##
## LEF for PtnCells ;
## created by Innovus v15.23-s045_1 on Thu Mar  5 10:42:21 2026
##

VERSION 5.8 ;

BUSBITCHARS "[]" ;
DIVIDERCHAR "/" ;

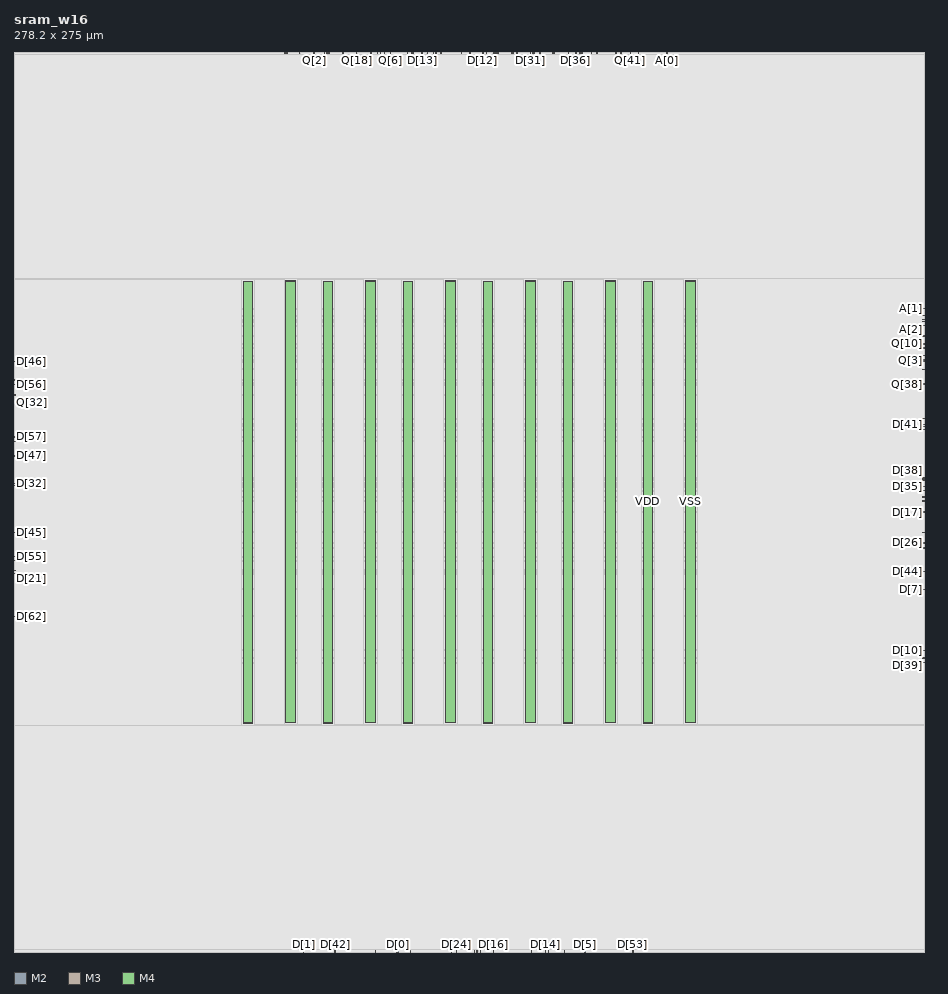
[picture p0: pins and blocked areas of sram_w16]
MACRO sram_w16
  CLASS BLOCK ;
  SIZE 278.2000 BY 275.0000 ;
  FOREIGN sram_w16 0.0000 0.0000 ;
  ORIGIN 0 0 ;
  SYMMETRY X Y R90 ;
  PIN CLK
    DIRECTION INPUT ;
    USE SIGNAL ;
    PORT
      LAYER M2 ;
        RECT 141.4500 0.0000 141.5500 0.5200 ;
    END
  END CLK
  PIN D[63]
    DIRECTION INPUT ;
    USE SIGNAL ;
    PORT
      LAYER M2 ;
        RECT 116.8500 0.0000 116.9500 0.5200 ;
    END
  END D[63]
  PIN D[62]
    DIRECTION INPUT ;
    USE SIGNAL ;
    PORT
      LAYER M3 ;
        RECT 0.0000 102.5500 0.5200 102.6500 ;
    END
  END D[62]
  PIN D[61]
    DIRECTION INPUT ;
    USE SIGNAL ;
    PORT
      LAYER M2 ;
        RECT 146.6500 274.4800 146.7500 275.0000 ;
    END
  END D[61]
  PIN D[60]
    DIRECTION INPUT ;
    USE SIGNAL ;
    PORT
      LAYER M3 ;
        RECT 277.6800 140.9500 278.2000 141.0500 ;
    END
  END D[60]
  PIN D[59]
    DIRECTION INPUT ;
    USE SIGNAL ;
    PORT
      LAYER M2 ;
        RECT 176.4500 274.4800 176.5500 275.0000 ;
    END
  END D[59]
  PIN D[58]
    DIRECTION INPUT ;
    USE SIGNAL ;
    PORT
      LAYER M3 ;
        RECT 0.0000 174.7500 0.5200 174.8500 ;
    END
  END D[58]
  PIN D[57]
    DIRECTION INPUT ;
    USE SIGNAL ;
    PORT
      LAYER M3 ;
        RECT 0.0000 157.3500 0.5200 157.4500 ;
    END
  END D[57]
  PIN D[56]
    DIRECTION INPUT ;
    USE SIGNAL ;
    PORT
      LAYER M3 ;
        RECT 0.0000 173.3500 0.5200 173.4500 ;
    END
  END D[56]
  PIN D[55]
    DIRECTION INPUT ;
    USE SIGNAL ;
    PORT
      LAYER M3 ;
        RECT 0.0000 120.7500 0.5200 120.8500 ;
    END
  END D[55]
  PIN D[54]
    DIRECTION INPUT ;
    USE SIGNAL ;
    PORT
      LAYER M2 ;
        RECT 142.4500 0.0000 142.5500 0.5200 ;
    END
  END D[54]
  PIN D[53]
    DIRECTION INPUT ;
    USE SIGNAL ;
    PORT
      LAYER M2 ;
        RECT 189.0500 0.0000 189.1500 0.5200 ;
    END
  END D[53]
  PIN D[52]
    DIRECTION INPUT ;
    USE SIGNAL ;
    PORT
      LAYER M3 ;
        RECT 277.6800 159.5500 278.2000 159.6500 ;
    END
  END D[52]
  PIN D[51]
    DIRECTION INPUT ;
    USE SIGNAL ;
    PORT
      LAYER M3 ;
        RECT 277.6800 88.3500 278.2000 88.4500 ;
    END
  END D[51]
  PIN D[50]
    DIRECTION INPUT ;
    USE SIGNAL ;
    PORT
      LAYER M4 ;
        RECT 141.6500 0.0000 141.7500 0.5200 ;
    END
  END D[50]
  PIN D[49]
    DIRECTION INPUT ;
    USE SIGNAL ;
    PORT
      LAYER M3 ;
        RECT 277.6800 144.1500 278.2000 144.2500 ;
    END
  END D[49]
  PIN D[48]
    DIRECTION INPUT ;
    USE SIGNAL ;
    PORT
      LAYER M3 ;
        RECT 0.0000 142.5500 0.5200 142.6500 ;
    END
  END D[48]
  PIN D[47]
    DIRECTION INPUT ;
    USE SIGNAL ;
    PORT
      LAYER M3 ;
        RECT 0.0000 151.5500 0.5200 151.6500 ;
    END
  END D[47]
  PIN D[46]
    DIRECTION INPUT ;
    USE SIGNAL ;
    PORT
      LAYER M3 ;
        RECT 0.0000 180.3500 0.5200 180.4500 ;
    END
  END D[46]
  PIN D[45]
    DIRECTION INPUT ;
    USE SIGNAL ;
    PORT
      LAYER M3 ;
        RECT 0.0000 128.1500 0.5200 128.2500 ;
    END
  END D[45]
  PIN D[44]
    DIRECTION INPUT ;
    USE SIGNAL ;
    PORT
      LAYER M3 ;
        RECT 277.6800 116.1500 278.2000 116.2500 ;
    END
  END D[44]
  PIN D[43]
    DIRECTION INPUT ;
    USE SIGNAL ;
    PORT
      LAYER M3 ;
        RECT 0.0000 115.5500 0.5200 115.6500 ;
    END
  END D[43]
  PIN D[42]
    DIRECTION INPUT ;
    USE SIGNAL ;
    PORT
      LAYER M2 ;
        RECT 98.0500 0.0000 98.1500 0.5200 ;
    END
  END D[42]
  PIN D[41]
    DIRECTION INPUT ;
    USE SIGNAL ;
    PORT
      LAYER M3 ;
        RECT 277.6800 161.1500 278.2000 161.2500 ;
    END
  END D[41]
  PIN D[40]
    DIRECTION INPUT ;
    USE SIGNAL ;
    PORT
      LAYER M2 ;
        RECT 140.6500 0.0000 140.7500 0.5200 ;
    END
  END D[40]
  PIN D[39]
    DIRECTION INPUT ;
    USE SIGNAL ;
    PORT
      LAYER M3 ;
        RECT 277.6800 89.7500 278.2000 89.8500 ;
    END
  END D[39]
  PIN D[38]
    DIRECTION INPUT ;
    USE SIGNAL ;
    PORT
      LAYER M3 ;
        RECT 277.6800 144.7500 278.2000 144.8500 ;
    END
  END D[38]
  PIN D[37]
    DIRECTION INPUT ;
    USE SIGNAL ;
    PORT
      LAYER M2 ;
        RECT 158.4500 274.4800 158.5500 275.0000 ;
    END
  END D[37]
  PIN D[36]
    DIRECTION INPUT ;
    USE SIGNAL ;
    PORT
      LAYER M2 ;
        RECT 171.6500 274.4800 171.7500 275.0000 ;
    END
  END D[36]
  PIN D[35]
    DIRECTION INPUT ;
    USE SIGNAL ;
    PORT
      LAYER M3 ;
        RECT 277.6800 142.1500 278.2000 142.2500 ;
    END
  END D[35]
  PIN D[34]
    DIRECTION INPUT ;
    USE SIGNAL ;
    PORT
      LAYER M2 ;
        RECT 164.6500 274.4800 164.7500 275.0000 ;
    END
  END D[34]
  PIN D[33]
    DIRECTION INPUT ;
    USE SIGNAL ;
    PORT
      LAYER M2 ;
        RECT 128.8500 274.4800 128.9500 275.0000 ;
    END
  END D[33]
  PIN D[32]
    DIRECTION INPUT ;
    USE SIGNAL ;
    PORT
      LAYER M3 ;
        RECT 0.0000 143.1500 0.5200 143.2500 ;
    END
  END D[32]
  PIN D[31]
    DIRECTION INPUT ;
    USE SIGNAL ;
    PORT
      LAYER M2 ;
        RECT 157.8500 274.4800 157.9500 275.0000 ;
    END
  END D[31]
  PIN D[30]
    DIRECTION INPUT ;
    USE SIGNAL ;
    PORT
      LAYER M2 ;
        RECT 144.2500 274.4800 144.3500 275.0000 ;
    END
  END D[30]
  PIN D[29]
    DIRECTION INPUT ;
    USE SIGNAL ;
    PORT
      LAYER M2 ;
        RECT 185.4500 274.4800 185.5500 275.0000 ;
    END
  END D[29]
  PIN D[28]
    DIRECTION INPUT ;
    USE SIGNAL ;
    PORT
      LAYER M3 ;
        RECT 277.6800 128.1500 278.2000 128.2500 ;
    END
  END D[28]
  PIN D[27]
    DIRECTION INPUT ;
    USE SIGNAL ;
    PORT
      LAYER M4 ;
        RECT 146.4500 274.4800 146.5500 275.0000 ;
    END
  END D[27]
  PIN D[26]
    DIRECTION INPUT ;
    USE SIGNAL ;
    PORT
      LAYER M3 ;
        RECT 277.6800 124.9500 278.2000 125.0500 ;
    END
  END D[26]
  PIN D[25]
    DIRECTION INPUT ;
    USE SIGNAL ;
    PORT
      LAYER M2 ;
        RECT 128.0500 274.4800 128.1500 275.0000 ;
    END
  END D[25]
  PIN D[24]
    DIRECTION INPUT ;
    USE SIGNAL ;
    PORT
      LAYER M2 ;
        RECT 135.2500 0.0000 135.3500 0.5200 ;
    END
  END D[24]
  PIN D[23]
    DIRECTION INPUT ;
    USE SIGNAL ;
    PORT
      LAYER M2 ;
        RECT 168.2500 0.0000 168.3500 0.5200 ;
    END
  END D[23]
  PIN D[22]
    DIRECTION INPUT ;
    USE SIGNAL ;
    PORT
      LAYER M2 ;
        RECT 111.0500 274.4800 111.1500 275.0000 ;
    END
  END D[22]
  PIN D[21]
    DIRECTION INPUT ;
    USE SIGNAL ;
    PORT
      LAYER M3 ;
        RECT 0.0000 116.5500 0.5200 116.6500 ;
    END
  END D[21]
  PIN D[20]
    DIRECTION INPUT ;
    USE SIGNAL ;
    PORT
      LAYER M2 ;
        RECT 111.8500 274.4800 111.9500 275.0000 ;
    END
  END D[20]
  PIN D[19]
    DIRECTION INPUT ;
    USE SIGNAL ;
    PORT
      LAYER M2 ;
        RECT 158.0500 0.0000 158.1500 0.5200 ;
    END
  END D[19]
  PIN D[18]
    DIRECTION INPUT ;
    USE SIGNAL ;
    PORT
      LAYER M2 ;
        RECT 94.8500 274.4800 94.9500 275.0000 ;
    END
  END D[18]
  PIN D[17]
    DIRECTION INPUT ;
    USE SIGNAL ;
    PORT
      LAYER M3 ;
        RECT 277.6800 134.3500 278.2000 134.4500 ;
    END
  END D[17]
  PIN D[16]
    DIRECTION INPUT ;
    USE SIGNAL ;
    PORT
      LAYER M2 ;
        RECT 146.4500 0.0000 146.5500 0.5200 ;
    END
  END D[16]
  PIN D[15]
    DIRECTION INPUT ;
    USE SIGNAL ;
    PORT
      LAYER M2 ;
        RECT 163.2500 0.0000 163.3500 0.5200 ;
    END
  END D[15]
  PIN D[14]
    DIRECTION INPUT ;
    USE SIGNAL ;
    PORT
      LAYER M2 ;
        RECT 162.2500 0.0000 162.3500 0.5200 ;
    END
  END D[14]
  PIN D[13]
    DIRECTION INPUT ;
    USE SIGNAL ;
    PORT
      LAYER M2 ;
        RECT 124.6500 274.4800 124.7500 275.0000 ;
    END
  END D[13]
  PIN D[12]
    DIRECTION INPUT ;
    USE SIGNAL ;
    PORT
      LAYER M2 ;
        RECT 143.2500 274.4800 143.3500 275.0000 ;
    END
  END D[12]
  PIN D[11]
    DIRECTION INPUT ;
    USE SIGNAL ;
    PORT
      LAYER M2 ;
        RECT 130.4500 274.4800 130.5500 275.0000 ;
    END
  END D[11]
  PIN D[10]
    DIRECTION INPUT ;
    USE SIGNAL ;
    PORT
      LAYER M3 ;
        RECT 277.6800 92.1500 278.2000 92.2500 ;
    END
  END D[10]
  PIN D[9]
    DIRECTION INPUT ;
    USE SIGNAL ;
    PORT
      LAYER M3 ;
        RECT 0.0000 155.9500 0.5200 156.0500 ;
    END
  END D[9]
  PIN D[8]
    DIRECTION INPUT ;
    USE SIGNAL ;
    PORT
      LAYER M2 ;
        RECT 133.6500 0.0000 133.7500 0.5200 ;
    END
  END D[8]
  PIN D[7]
    DIRECTION INPUT ;
    USE SIGNAL ;
    PORT
      LAYER M3 ;
        RECT 277.6800 110.7500 278.2000 110.8500 ;
    END
  END D[7]
  PIN D[6]
    DIRECTION INPUT ;
    USE SIGNAL ;
    PORT
      LAYER M2 ;
        RECT 121.0500 0.0000 121.1500 0.5200 ;
    END
  END D[6]
  PIN D[5]
    DIRECTION INPUT ;
    USE SIGNAL ;
    PORT
      LAYER M2 ;
        RECT 174.4500 0.0000 174.5500 0.5200 ;
    END
  END D[5]
  PIN D[4]
    DIRECTION INPUT ;
    USE SIGNAL ;
    PORT
      LAYER M2 ;
        RECT 110.4500 0.0000 110.5500 0.5200 ;
    END
  END D[4]
  PIN D[3]
    DIRECTION INPUT ;
    USE SIGNAL ;
    PORT
      LAYER M3 ;
        RECT 277.6800 177.9500 278.2000 178.0500 ;
    END
  END D[3]
  PIN D[2]
    DIRECTION INPUT ;
    USE SIGNAL ;
    PORT
      LAYER M3 ;
        RECT 0.0000 119.5500 0.5200 119.6500 ;
    END
  END D[2]
  PIN D[1]
    DIRECTION INPUT ;
    USE SIGNAL ;
    PORT
      LAYER M2 ;
        RECT 88.4500 0.0000 88.5500 0.5200 ;
    END
  END D[1]
  PIN D[0]
    DIRECTION INPUT ;
    USE SIGNAL ;
    PORT
      LAYER M2 ;
        RECT 117.2500 0.0000 117.3500 0.5200 ;
    END
  END D[0]
  PIN Q[63]
    DIRECTION OUTPUT ;
    USE SIGNAL ;
    PORT
      LAYER M2 ;
        RECT 121.8500 274.4800 121.9500 275.0000 ;
    END
  END Q[63]
  PIN Q[62]
    DIRECTION OUTPUT ;
    USE SIGNAL ;
    PORT
      LAYER M2 ;
        RECT 83.0500 274.4800 83.1500 275.0000 ;
    END
  END Q[62]
  PIN Q[61]
    DIRECTION OUTPUT ;
    USE SIGNAL ;
    PORT
      LAYER M2 ;
        RECT 147.8500 274.4800 147.9500 275.0000 ;
    END
  END Q[61]
  PIN Q[60]
    DIRECTION OUTPUT ;
    USE SIGNAL ;
    PORT
      LAYER M3 ;
        RECT 277.6800 162.9500 278.2000 163.0500 ;
    END
  END Q[60]
  PIN Q[59]
    DIRECTION OUTPUT ;
    USE SIGNAL ;
    PORT
      LAYER M2 ;
        RECT 183.8500 274.4800 183.9500 275.0000 ;
    END
  END Q[59]
  PIN Q[58]
    DIRECTION OUTPUT ;
    USE SIGNAL ;
    PORT
      LAYER M2 ;
        RECT 87.2500 274.4800 87.3500 275.0000 ;
    END
  END Q[58]
  PIN Q[57]
    DIRECTION OUTPUT ;
    USE SIGNAL ;
    PORT
      LAYER M2 ;
        RECT 113.2500 274.4800 113.3500 275.0000 ;
    END
  END Q[57]
  PIN Q[56]
    DIRECTION OUTPUT ;
    USE SIGNAL ;
    PORT
      LAYER M2 ;
        RECT 95.8500 274.4800 95.9500 275.0000 ;
    END
  END Q[56]
  PIN Q[55]
    DIRECTION OUTPUT ;
    USE SIGNAL ;
    PORT
      LAYER M4 ;
        RECT 95.8500 274.4800 95.9500 275.0000 ;
    END
  END Q[55]
  PIN Q[54]
    DIRECTION OUTPUT ;
    USE SIGNAL ;
    PORT
      LAYER M2 ;
        RECT 147.0500 274.4800 147.1500 275.0000 ;
    END
  END Q[54]
  PIN Q[53]
    DIRECTION OUTPUT ;
    USE SIGNAL ;
    PORT
      LAYER M3 ;
        RECT 277.6800 160.5500 278.2000 160.6500 ;
    END
  END Q[53]
  PIN Q[52]
    DIRECTION OUTPUT ;
    USE SIGNAL ;
    PORT
      LAYER M2 ;
        RECT 190.8500 274.4800 190.9500 275.0000 ;
    END
  END Q[52]
  PIN Q[51]
    DIRECTION OUTPUT ;
    USE SIGNAL ;
    PORT
      LAYER M3 ;
        RECT 277.6800 180.9500 278.2000 181.0500 ;
    END
  END Q[51]
  PIN Q[50]
    DIRECTION OUTPUT ;
    USE SIGNAL ;
    PORT
      LAYER M4 ;
        RECT 164.8500 274.4800 164.9500 275.0000 ;
    END
  END Q[50]
  PIN Q[49]
    DIRECTION OUTPUT ;
    USE SIGNAL ;
    PORT
      LAYER M3 ;
        RECT 277.6800 182.1500 278.2000 182.2500 ;
    END
  END Q[49]
  PIN Q[48]
    DIRECTION OUTPUT ;
    USE SIGNAL ;
    PORT
      LAYER M2 ;
        RECT 100.6500 274.4800 100.7500 275.0000 ;
    END
  END Q[48]
  PIN Q[47]
    DIRECTION OUTPUT ;
    USE SIGNAL ;
    PORT
      LAYER M4 ;
        RECT 83.0500 274.4800 83.1500 275.0000 ;
    END
  END Q[47]
  PIN Q[46]
    DIRECTION OUTPUT ;
    USE SIGNAL ;
    PORT
      LAYER M2 ;
        RECT 95.4500 274.4800 95.5500 275.0000 ;
    END
  END Q[46]
  PIN Q[45]
    DIRECTION OUTPUT ;
    USE SIGNAL ;
    PORT
      LAYER M4 ;
        RECT 130.4500 274.4800 130.5500 275.0000 ;
    END
  END Q[45]
  PIN Q[44]
    DIRECTION OUTPUT ;
    USE SIGNAL ;
    PORT
      LAYER M3 ;
        RECT 277.6800 173.7500 278.2000 173.8500 ;
    END
  END Q[44]
  PIN Q[43]
    DIRECTION OUTPUT ;
    USE SIGNAL ;
    PORT
      LAYER M4 ;
        RECT 87.2500 274.4800 87.3500 275.0000 ;
    END
  END Q[43]
  PIN Q[42]
    DIRECTION OUTPUT ;
    USE SIGNAL ;
    PORT
      LAYER M2 ;
        RECT 82.6500 274.4800 82.7500 275.0000 ;
    END
  END Q[42]
  PIN Q[41]
    DIRECTION OUTPUT ;
    USE SIGNAL ;
    PORT
      LAYER M2 ;
        RECT 188.2500 274.4800 188.3500 275.0000 ;
    END
  END Q[41]
  PIN Q[40]
    DIRECTION OUTPUT ;
    USE SIGNAL ;
    PORT
      LAYER M2 ;
        RECT 153.6500 274.4800 153.7500 275.0000 ;
    END
  END Q[40]
  PIN Q[39]
    DIRECTION OUTPUT ;
    USE SIGNAL ;
    PORT
      LAYER M3 ;
        RECT 277.6800 185.7500 278.2000 185.8500 ;
    END
  END Q[39]
  PIN Q[38]
    DIRECTION OUTPUT ;
    USE SIGNAL ;
    PORT
      LAYER M3 ;
        RECT 277.6800 173.3500 278.2000 173.4500 ;
    END
  END Q[38]
  PIN Q[37]
    DIRECTION OUTPUT ;
    USE SIGNAL ;
    PORT
      LAYER M2 ;
        RECT 152.0500 274.4800 152.1500 275.0000 ;
    END
  END Q[37]
  PIN Q[36]
    DIRECTION OUTPUT ;
    USE SIGNAL ;
    PORT
      LAYER M2 ;
        RECT 173.6500 274.4800 173.7500 275.0000 ;
    END
  END Q[36]
  PIN Q[35]
    DIRECTION OUTPUT ;
    USE SIGNAL ;
    PORT
      LAYER M2 ;
        RECT 169.4500 274.4800 169.5500 275.0000 ;
    END
  END Q[35]
  PIN Q[34]
    DIRECTION OUTPUT ;
    USE SIGNAL ;
    PORT
      LAYER M2 ;
        RECT 158.8500 274.4800 158.9500 275.0000 ;
    END
  END Q[34]
  PIN Q[33]
    DIRECTION OUTPUT ;
    USE SIGNAL ;
    PORT
      LAYER M2 ;
        RECT 139.2500 274.4800 139.3500 275.0000 ;
    END
  END Q[33]
  PIN Q[32]
    DIRECTION OUTPUT ;
    USE SIGNAL ;
    PORT
      LAYER M3 ;
        RECT 0.0000 170.1500 0.5200 170.2500 ;
    END
  END Q[32]
  PIN Q[31]
    DIRECTION OUTPUT ;
    USE SIGNAL ;
    PORT
      LAYER M2 ;
        RECT 160.6500 274.4800 160.7500 275.0000 ;
    END
  END Q[31]
  PIN Q[30]
    DIRECTION OUTPUT ;
    USE SIGNAL ;
    PORT
      LAYER M4 ;
        RECT 147.2500 274.4800 147.3500 275.0000 ;
    END
  END Q[30]
  PIN Q[29]
    DIRECTION OUTPUT ;
    USE SIGNAL ;
    PORT
      LAYER M2 ;
        RECT 178.0500 274.4800 178.1500 275.0000 ;
    END
  END Q[29]
  PIN Q[28]
    DIRECTION OUTPUT ;
    USE SIGNAL ;
    PORT
      LAYER M2 ;
        RECT 165.0500 274.4800 165.1500 275.0000 ;
    END
  END Q[28]
  PIN Q[27]
    DIRECTION OUTPUT ;
    USE SIGNAL ;
    PORT
      LAYER M2 ;
        RECT 152.4500 274.4800 152.5500 275.0000 ;
    END
  END Q[27]
  PIN Q[26]
    DIRECTION OUTPUT ;
    USE SIGNAL ;
    PORT
      LAYER M3 ;
        RECT 277.6800 138.9500 278.2000 139.0500 ;
    END
  END Q[26]
  PIN Q[25]
    DIRECTION OUTPUT ;
    USE SIGNAL ;
    PORT
      LAYER M2 ;
        RECT 126.2500 274.4800 126.3500 275.0000 ;
    END
  END Q[25]
  PIN Q[24]
    DIRECTION OUTPUT ;
    USE SIGNAL ;
    PORT
      LAYER M4 ;
        RECT 126.2500 274.4800 126.3500 275.0000 ;
    END
  END Q[24]
  PIN Q[23]
    DIRECTION OUTPUT ;
    USE SIGNAL ;
    PORT
      LAYER M3 ;
        RECT 277.6800 123.3500 278.2000 123.4500 ;
    END
  END Q[23]
  PIN Q[22]
    DIRECTION OUTPUT ;
    USE SIGNAL ;
    PORT
      LAYER M4 ;
        RECT 100.4500 274.4800 100.5500 275.0000 ;
    END
  END Q[22]
  PIN Q[21]
    DIRECTION OUTPUT ;
    USE SIGNAL ;
    PORT
      LAYER M2 ;
        RECT 104.6500 274.4800 104.7500 275.0000 ;
    END
  END Q[21]
  PIN Q[20]
    DIRECTION OUTPUT ;
    USE SIGNAL ;
    PORT
      LAYER M2 ;
        RECT 109.0500 274.4800 109.1500 275.0000 ;
    END
  END Q[20]
  PIN Q[19]
    DIRECTION OUTPUT ;
    USE SIGNAL ;
    PORT
      LAYER M4 ;
        RECT 152.0500 274.4800 152.1500 275.0000 ;
    END
  END Q[19]
  PIN Q[18]
    DIRECTION OUTPUT ;
    USE SIGNAL ;
    PORT
      LAYER M4 ;
        RECT 104.6500 274.4800 104.7500 275.0000 ;
    END
  END Q[18]
  PIN Q[17]
    DIRECTION OUTPUT ;
    USE SIGNAL ;
    PORT
      LAYER M3 ;
        RECT 277.6800 184.5500 278.2000 184.6500 ;
    END
  END Q[17]
  PIN Q[16]
    DIRECTION OUTPUT ;
    USE SIGNAL ;
    PORT
      LAYER M4 ;
        RECT 146.8500 274.4800 146.9500 275.0000 ;
    END
  END Q[16]
  PIN Q[15]
    DIRECTION OUTPUT ;
    USE SIGNAL ;
    PORT
      LAYER M4 ;
        RECT 173.6500 274.4800 173.7500 275.0000 ;
    END
  END Q[15]
  PIN Q[14]
    DIRECTION OUTPUT ;
    USE SIGNAL ;
    PORT
      LAYER M2 ;
        RECT 173.2500 274.4800 173.3500 275.0000 ;
    END
  END Q[14]
  PIN Q[13]
    DIRECTION OUTPUT ;
    USE SIGNAL ;
    PORT
      LAYER M4 ;
        RECT 109.0500 274.4800 109.1500 275.0000 ;
    END
  END Q[13]
  PIN Q[12]
    DIRECTION OUTPUT ;
    USE SIGNAL ;
    PORT
      LAYER M2 ;
        RECT 147.4500 274.4800 147.5500 275.0000 ;
    END
  END Q[12]
  PIN Q[11]
    DIRECTION OUTPUT ;
    USE SIGNAL ;
    PORT
      LAYER M2 ;
        RECT 120.2500 274.4800 120.3500 275.0000 ;
    END
  END Q[11]
  PIN Q[10]
    DIRECTION OUTPUT ;
    USE SIGNAL ;
    PORT
      LAYER M3 ;
        RECT 277.6800 188.1500 278.2000 188.2500 ;
    END
  END Q[10]
  PIN Q[9]
    DIRECTION OUTPUT ;
    USE SIGNAL ;
    PORT
      LAYER M2 ;
        RECT 83.4500 274.4800 83.5500 275.0000 ;
    END
  END Q[9]
  PIN Q[8]
    DIRECTION OUTPUT ;
    USE SIGNAL ;
    PORT
      LAYER M2 ;
        RECT 136.6500 274.4800 136.7500 275.0000 ;
    END
  END Q[8]
  PIN Q[7]
    DIRECTION OUTPUT ;
    USE SIGNAL ;
    PORT
      LAYER M3 ;
        RECT 277.6800 137.7500 278.2000 137.8500 ;
    END
  END Q[7]
  PIN Q[6]
    DIRECTION OUTPUT ;
    USE SIGNAL ;
    PORT
      LAYER M2 ;
        RECT 115.0500 274.4800 115.1500 275.0000 ;
    END
  END Q[6]
  PIN Q[5]
    DIRECTION OUTPUT ;
    USE SIGNAL ;
    PORT
      LAYER M2 ;
        RECT 172.8500 274.4800 172.9500 275.0000 ;
    END
  END Q[5]
  PIN Q[4]
    DIRECTION OUTPUT ;
    USE SIGNAL ;
    PORT
      LAYER M4 ;
        RECT 121.8500 274.4800 121.9500 275.0000 ;
    END
  END Q[4]
  PIN Q[3]
    DIRECTION OUTPUT ;
    USE SIGNAL ;
    PORT
      LAYER M3 ;
        RECT 277.6800 180.5500 278.2000 180.6500 ;
    END
  END Q[3]
  PIN Q[2]
    DIRECTION OUTPUT ;
    USE SIGNAL ;
    PORT
      LAYER M2 ;
        RECT 91.6500 274.4800 91.7500 275.0000 ;
    END
  END Q[2]
  PIN Q[1]
    DIRECTION OUTPUT ;
    USE SIGNAL ;
    PORT
      LAYER M2 ;
        RECT 96.2500 274.4800 96.3500 275.0000 ;
    END
  END Q[1]
  PIN Q[0]
    DIRECTION OUTPUT ;
    USE SIGNAL ;
    PORT
      LAYER M2 ;
        RECT 121.4500 274.4800 121.5500 275.0000 ;
    END
  END Q[0]
  PIN CEN
    DIRECTION INPUT ;
    USE SIGNAL ;
    PORT
      LAYER M3 ;
        RECT 277.6800 194.3500 278.2000 194.4500 ;
    END
  END CEN
  PIN WEN
    DIRECTION INPUT ;
    USE SIGNAL ;
    PORT
      LAYER M3 ;
        RECT 277.6800 191.3500 278.2000 191.4500 ;
    END
  END WEN
  PIN A[3]
    DIRECTION INPUT ;
    USE SIGNAL ;
    PORT
      LAYER M3 ;
        RECT 277.6800 193.1500 278.2000 193.2500 ;
    END
  END A[3]
  PIN A[2]
    DIRECTION INPUT ;
    USE SIGNAL ;
    PORT
      LAYER M3 ;
        RECT 277.6800 192.5500 278.2000 192.6500 ;
    END
  END A[2]
  PIN A[1]
    DIRECTION INPUT ;
    USE SIGNAL ;
    PORT
      LAYER M3 ;
        RECT 277.6800 196.5500 278.2000 196.6500 ;
    END
  END A[1]
  PIN A[0]
    DIRECTION INPUT ;
    USE SIGNAL ;
    PORT
      LAYER M2 ;
        RECT 199.4500 274.4800 199.5500 275.0000 ;
    END
  END A[0]
  PIN VSS
    DIRECTION INOUT ;
    USE GROUND ;

# P/G power stripe data as pin
    PORT
      LAYER M4 ;
        RECT 205.2000 70.0000 208.2000 205.0000 ;
        RECT 180.7600 70.0000 183.7600 205.0000 ;
        RECT 156.3200 70.0000 159.3200 205.0000 ;
        RECT 131.8800 70.0000 134.8800 205.0000 ;
        RECT 107.4400 70.0000 110.4400 205.0000 ;
        RECT 83.0000 70.0000 86.0000 205.0000 ;
        RECT 83.0000 204.8350 86.0000 205.1650 ;
        RECT 107.4400 204.8350 110.4400 205.1650 ;
        RECT 131.8800 204.8350 134.8800 205.1650 ;
        RECT 156.3200 204.8350 159.3200 205.1650 ;
        RECT 180.7600 204.8350 183.7600 205.1650 ;
        RECT 205.2000 204.8350 208.2000 205.1650 ;
    END
# end of P/G power stripe data as pin

  END VSS
  PIN VDD
    DIRECTION INOUT ;
    USE POWER ;

# P/G power stripe data as pin
    PORT
      LAYER M4 ;
        RECT 192.2000 70.0000 195.2000 205.0000 ;
        RECT 167.7600 70.0000 170.7600 205.0000 ;
        RECT 143.3200 70.0000 146.3200 205.0000 ;
        RECT 118.8800 70.0000 121.8800 205.0000 ;
        RECT 94.4400 70.0000 97.4400 205.0000 ;
        RECT 70.0000 70.0000 73.0000 205.0000 ;
        RECT 70.0000 69.8350 73.0000 70.1650 ;
        RECT 94.4400 69.8350 97.4400 70.1650 ;
        RECT 118.8800 69.8350 121.8800 70.1650 ;
        RECT 143.3200 69.8350 146.3200 70.1650 ;
        RECT 167.7600 69.8350 170.7600 70.1650 ;
        RECT 192.2000 69.8350 195.2000 70.1650 ;
    END
# end of P/G power stripe data as pin

  END VDD
  OBS
    LAYER M1 ;
      RECT 0.0000 0.0000 278.2000 275.0000 ;
    LAYER M2 ;
      RECT 199.6500 274.3800 278.2000 275.0000 ;
      RECT 191.0500 274.3800 199.3500 275.0000 ;
      RECT 188.4500 274.3800 190.7500 275.0000 ;
      RECT 185.6500 274.3800 188.1500 275.0000 ;
      RECT 184.0500 274.3800 185.3500 275.0000 ;
      RECT 178.2500 274.3800 183.7500 275.0000 ;
      RECT 176.6500 274.3800 177.9500 275.0000 ;
      RECT 173.8500 274.3800 176.3500 275.0000 ;
      RECT 173.4500 274.3800 173.5500 275.0000 ;
      RECT 173.0500 274.3800 173.1500 275.0000 ;
      RECT 171.8500 274.3800 172.7500 275.0000 ;
      RECT 169.6500 274.3800 171.5500 275.0000 ;
      RECT 165.2500 274.3800 169.3500 275.0000 ;
      RECT 164.8500 274.3800 164.9500 275.0000 ;
      RECT 160.8500 274.3800 164.5500 275.0000 ;
      RECT 159.0500 274.3800 160.5500 275.0000 ;
      RECT 158.6500 274.3800 158.7500 275.0000 ;
      RECT 158.0500 274.3800 158.3500 275.0000 ;
      RECT 153.8500 274.3800 157.7500 275.0000 ;
      RECT 152.6500 274.3800 153.5500 275.0000 ;
      RECT 152.2500 274.3800 152.3500 275.0000 ;
      RECT 148.0500 274.3800 151.9500 275.0000 ;
      RECT 147.6500 274.3800 147.7500 275.0000 ;
      RECT 147.2500 274.3800 147.3500 275.0000 ;
      RECT 146.8500 274.3800 146.9500 275.0000 ;
      RECT 144.4500 274.3800 146.5500 275.0000 ;
      RECT 143.4500 274.3800 144.1500 275.0000 ;
      RECT 139.4500 274.3800 143.1500 275.0000 ;
      RECT 136.8500 274.3800 139.1500 275.0000 ;
      RECT 130.6500 274.3800 136.5500 275.0000 ;
      RECT 129.0500 274.3800 130.3500 275.0000 ;
      RECT 128.2500 274.3800 128.7500 275.0000 ;
      RECT 126.4500 274.3800 127.9500 275.0000 ;
      RECT 124.8500 274.3800 126.1500 275.0000 ;
      RECT 122.0500 274.3800 124.5500 275.0000 ;
      RECT 121.6500 274.3800 121.7500 275.0000 ;
      RECT 120.4500 274.3800 121.3500 275.0000 ;
      RECT 115.2500 274.3800 120.1500 275.0000 ;
      RECT 113.4500 274.3800 114.9500 275.0000 ;
      RECT 112.0500 274.3800 113.1500 275.0000 ;
      RECT 111.2500 274.3800 111.7500 275.0000 ;
      RECT 109.2500 274.3800 110.9500 275.0000 ;
      RECT 104.8500 274.3800 108.9500 275.0000 ;
      RECT 100.8500 274.3800 104.5500 275.0000 ;
      RECT 96.4500 274.3800 100.5500 275.0000 ;
      RECT 96.0500 274.3800 96.1500 275.0000 ;
      RECT 95.6500 274.3800 95.7500 275.0000 ;
      RECT 95.0500 274.3800 95.3500 275.0000 ;
      RECT 91.8500 274.3800 94.7500 275.0000 ;
      RECT 87.4500 274.3800 91.5500 275.0000 ;
      RECT 83.6500 274.3800 87.1500 275.0000 ;
      RECT 83.2500 274.3800 83.3500 275.0000 ;
      RECT 82.8500 274.3800 82.9500 275.0000 ;
      RECT 0.0000 274.3800 82.5500 275.0000 ;
      RECT 0.0000 0.6200 278.2000 274.3800 ;
      RECT 189.2500 0.0000 278.2000 0.6200 ;
      RECT 174.6500 0.0000 188.9500 0.6200 ;
      RECT 168.4500 0.0000 174.3500 0.6200 ;
      RECT 163.4500 0.0000 168.1500 0.6200 ;
      RECT 162.4500 0.0000 163.1500 0.6200 ;
      RECT 158.2500 0.0000 162.1500 0.6200 ;
      RECT 146.6500 0.0000 157.9500 0.6200 ;
      RECT 142.6500 0.0000 146.3500 0.6200 ;
      RECT 141.6500 0.0000 142.3500 0.6200 ;
      RECT 140.8500 0.0000 141.3500 0.6200 ;
      RECT 135.4500 0.0000 140.5500 0.6200 ;
      RECT 133.8500 0.0000 135.1500 0.6200 ;
      RECT 121.2500 0.0000 133.5500 0.6200 ;
      RECT 117.4500 0.0000 120.9500 0.6200 ;
      RECT 117.0500 0.0000 117.1500 0.6200 ;
      RECT 110.6500 0.0000 116.7500 0.6200 ;
      RECT 98.2500 0.0000 110.3500 0.6200 ;
      RECT 88.6500 0.0000 97.9500 0.6200 ;
      RECT 0.0000 0.0000 88.3500 0.6200 ;
    LAYER M3 ;
      RECT 0.0000 196.7500 278.2000 275.0000 ;
      RECT 0.0000 196.4500 277.5800 196.7500 ;
      RECT 0.0000 194.5500 278.2000 196.4500 ;
      RECT 0.0000 194.2500 277.5800 194.5500 ;
      RECT 0.0000 193.3500 278.2000 194.2500 ;
      RECT 0.0000 193.0500 277.5800 193.3500 ;
      RECT 0.0000 192.7500 278.2000 193.0500 ;
      RECT 0.0000 192.4500 277.5800 192.7500 ;
      RECT 0.0000 191.5500 278.2000 192.4500 ;
      RECT 0.0000 191.2500 277.5800 191.5500 ;
      RECT 0.0000 188.3500 278.2000 191.2500 ;
      RECT 0.0000 188.0500 277.5800 188.3500 ;
      RECT 0.0000 185.9500 278.2000 188.0500 ;
      RECT 0.0000 185.6500 277.5800 185.9500 ;
      RECT 0.0000 184.7500 278.2000 185.6500 ;
      RECT 0.0000 184.4500 277.5800 184.7500 ;
      RECT 0.0000 182.3500 278.2000 184.4500 ;
      RECT 0.0000 182.0500 277.5800 182.3500 ;
      RECT 0.0000 181.1500 278.2000 182.0500 ;
      RECT 0.0000 180.8500 277.5800 181.1500 ;
      RECT 0.0000 180.7500 278.2000 180.8500 ;
      RECT 0.0000 180.5500 277.5800 180.7500 ;
      RECT 0.6200 180.4500 277.5800 180.5500 ;
      RECT 0.6200 180.2500 278.2000 180.4500 ;
      RECT 0.0000 178.1500 278.2000 180.2500 ;
      RECT 0.0000 177.8500 277.5800 178.1500 ;
      RECT 0.0000 174.9500 278.2000 177.8500 ;
      RECT 0.6200 174.6500 278.2000 174.9500 ;
      RECT 0.0000 173.9500 278.2000 174.6500 ;
      RECT 0.0000 173.6500 277.5800 173.9500 ;
      RECT 0.0000 173.5500 278.2000 173.6500 ;
      RECT 0.6200 173.2500 277.5800 173.5500 ;
      RECT 0.0000 170.3500 278.2000 173.2500 ;
      RECT 0.6200 170.0500 278.2000 170.3500 ;
      RECT 0.0000 163.1500 278.2000 170.0500 ;
      RECT 0.0000 162.8500 277.5800 163.1500 ;
      RECT 0.0000 161.3500 278.2000 162.8500 ;
      RECT 0.0000 161.0500 277.5800 161.3500 ;
      RECT 0.0000 160.7500 278.2000 161.0500 ;
      RECT 0.0000 160.4500 277.5800 160.7500 ;
      RECT 0.0000 159.7500 278.2000 160.4500 ;
      RECT 0.0000 159.4500 277.5800 159.7500 ;
      RECT 0.0000 157.5500 278.2000 159.4500 ;
      RECT 0.6200 157.2500 278.2000 157.5500 ;
      RECT 0.0000 156.1500 278.2000 157.2500 ;
      RECT 0.6200 155.8500 278.2000 156.1500 ;
      RECT 0.0000 151.7500 278.2000 155.8500 ;
      RECT 0.6200 151.4500 278.2000 151.7500 ;
      RECT 0.0000 144.9500 278.2000 151.4500 ;
      RECT 0.0000 144.6500 277.5800 144.9500 ;
      RECT 0.0000 144.3500 278.2000 144.6500 ;
      RECT 0.0000 144.0500 277.5800 144.3500 ;
      RECT 0.0000 143.3500 278.2000 144.0500 ;
      RECT 0.6200 143.0500 278.2000 143.3500 ;
      RECT 0.0000 142.7500 278.2000 143.0500 ;
      RECT 0.6200 142.4500 278.2000 142.7500 ;
      RECT 0.0000 142.3500 278.2000 142.4500 ;
      RECT 0.0000 142.0500 277.5800 142.3500 ;
      RECT 0.0000 141.1500 278.2000 142.0500 ;
      RECT 0.0000 140.8500 277.5800 141.1500 ;
      RECT 0.0000 139.1500 278.2000 140.8500 ;
      RECT 0.0000 138.8500 277.5800 139.1500 ;
      RECT 0.0000 137.9500 278.2000 138.8500 ;
      RECT 0.0000 137.6500 277.5800 137.9500 ;
      RECT 0.0000 134.5500 278.2000 137.6500 ;
      RECT 0.0000 134.2500 277.5800 134.5500 ;
      RECT 0.0000 128.3500 278.2000 134.2500 ;
      RECT 0.6200 128.0500 277.5800 128.3500 ;
      RECT 0.0000 125.1500 278.2000 128.0500 ;
      RECT 0.0000 124.8500 277.5800 125.1500 ;
      RECT 0.0000 123.5500 278.2000 124.8500 ;
      RECT 0.0000 123.2500 277.5800 123.5500 ;
      RECT 0.0000 120.9500 278.2000 123.2500 ;
      RECT 0.6200 120.6500 278.2000 120.9500 ;
      RECT 0.0000 119.7500 278.2000 120.6500 ;
      RECT 0.6200 119.4500 278.2000 119.7500 ;
      RECT 0.0000 116.7500 278.2000 119.4500 ;
      RECT 0.6200 116.4500 278.2000 116.7500 ;
      RECT 0.0000 116.3500 278.2000 116.4500 ;
      RECT 0.0000 116.0500 277.5800 116.3500 ;
      RECT 0.0000 115.7500 278.2000 116.0500 ;
      RECT 0.6200 115.4500 278.2000 115.7500 ;
      RECT 0.0000 110.9500 278.2000 115.4500 ;
      RECT 0.0000 110.6500 277.5800 110.9500 ;
      RECT 0.0000 102.7500 278.2000 110.6500 ;
      RECT 0.6200 102.4500 278.2000 102.7500 ;
      RECT 0.0000 92.3500 278.2000 102.4500 ;
      RECT 0.0000 92.0500 277.5800 92.3500 ;
      RECT 0.0000 89.9500 278.2000 92.0500 ;
      RECT 0.0000 89.6500 277.5800 89.9500 ;
      RECT 0.0000 88.5500 278.2000 89.6500 ;
      RECT 0.0000 88.2500 277.5800 88.5500 ;
      RECT 0.0000 0.0000 278.2000 88.2500 ;
    LAYER M4 ;
      RECT 173.8500 274.3800 278.2000 275.0000 ;
      RECT 165.0500 274.3800 173.5500 275.0000 ;
      RECT 152.2500 274.3800 164.7500 275.0000 ;
      RECT 147.4500 274.3800 151.9500 275.0000 ;
      RECT 147.0500 274.3800 147.1500 275.0000 ;
      RECT 146.6500 274.3800 146.7500 275.0000 ;
      RECT 130.6500 274.3800 146.3500 275.0000 ;
      RECT 126.4500 274.3800 130.3500 275.0000 ;
      RECT 122.0500 274.3800 126.1500 275.0000 ;
      RECT 109.2500 274.3800 121.7500 275.0000 ;
      RECT 104.8500 274.3800 108.9500 275.0000 ;
      RECT 100.6500 274.3800 104.5500 275.0000 ;
      RECT 96.0500 274.3800 100.3500 275.0000 ;
      RECT 87.4500 274.3800 95.7500 275.0000 ;
      RECT 83.2500 274.3800 87.1500 275.0000 ;
      RECT 0.0000 274.3800 82.9500 275.0000 ;
      RECT 0.0000 205.6650 278.2000 274.3800 ;
      RECT 184.2600 205.5000 204.7000 205.6650 ;
      RECT 159.8200 205.5000 180.2600 205.6650 ;
      RECT 135.3800 205.5000 155.8200 205.6650 ;
      RECT 110.9400 205.5000 131.3800 205.6650 ;
      RECT 86.5000 205.5000 106.9400 205.6650 ;
      RECT 0.0000 205.5000 82.5000 205.6650 ;
      RECT 208.7000 69.5000 278.2000 205.6650 ;
      RECT 195.7000 69.5000 204.7000 205.5000 ;
      RECT 184.2600 69.5000 191.7000 205.5000 ;
      RECT 171.2600 69.5000 180.2600 205.5000 ;
      RECT 159.8200 69.5000 167.2600 205.5000 ;
      RECT 146.8200 69.5000 155.8200 205.5000 ;
      RECT 135.3800 69.5000 142.8200 205.5000 ;
      RECT 122.3800 69.5000 131.3800 205.5000 ;
      RECT 110.9400 69.5000 118.3800 205.5000 ;
      RECT 97.9400 69.5000 106.9400 205.5000 ;
      RECT 86.5000 69.5000 93.9400 205.5000 ;
      RECT 73.5000 69.5000 82.5000 205.5000 ;
      RECT 195.7000 69.3350 278.2000 69.5000 ;
      RECT 171.2600 69.3350 191.7000 69.5000 ;
      RECT 146.8200 69.3350 167.2600 69.5000 ;
      RECT 122.3800 69.3350 142.8200 69.5000 ;
      RECT 97.9400 69.3350 118.3800 69.5000 ;
      RECT 73.5000 69.3350 93.9400 69.5000 ;
      RECT 0.0000 69.3350 69.5000 205.5000 ;
      RECT 0.0000 0.6200 278.2000 69.3350 ;
      RECT 141.8500 0.0000 278.2000 0.6200 ;
      RECT 0.0000 0.0000 141.5500 0.6200 ;
  END
END sram_w16

END LIBRARY
